VERSION 5.7 ;
BUSBITCHARS "[]" ;
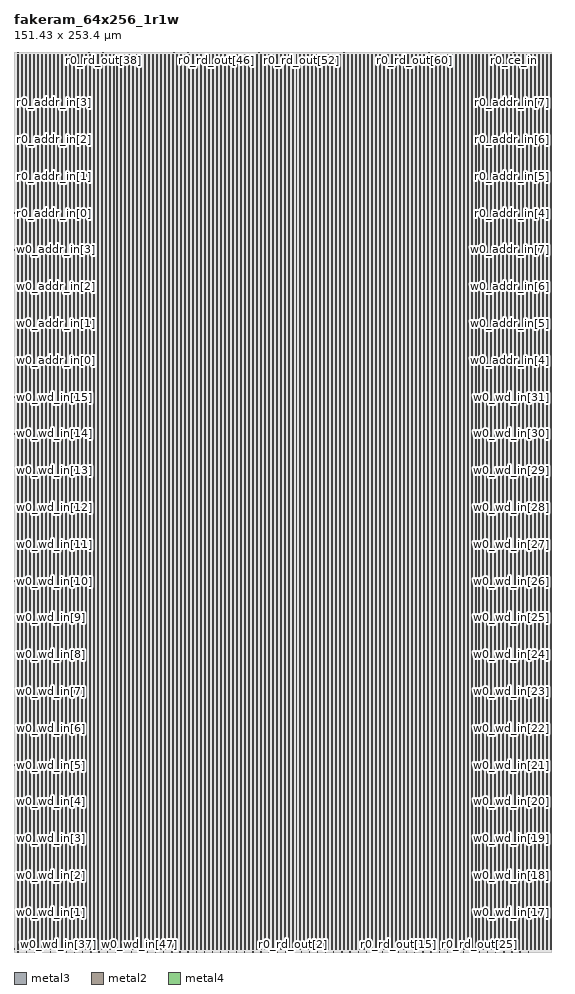
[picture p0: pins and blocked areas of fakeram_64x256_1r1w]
MACRO fakeram_64x256_1r1w
  FOREIGN fakeram_64x256_1r1w 0 0 ;
  SYMMETRY X Y R90 ;
  SIZE 151.430 BY 253.400 ;
  CLASS BLOCK ;
  PIN w0_wd_in[0]
    DIRECTION INPUT ;
    USE SIGNAL ;
    SHAPE ABUTMENT ;
    PORT
      LAYER metal3 ;
      RECT 0.000 0.805 0.210 0.875 ;
    END
  END w0_wd_in[0]
  PIN w0_wd_in[1]
    DIRECTION INPUT ;
    USE SIGNAL ;
    SHAPE ABUTMENT ;
    PORT
      LAYER metal3 ;
      RECT 0.000 11.165 0.210 11.235 ;
    END
  END w0_wd_in[1]
  PIN w0_wd_in[2]
    DIRECTION INPUT ;
    USE SIGNAL ;
    SHAPE ABUTMENT ;
    PORT
      LAYER metal3 ;
      RECT 0.000 21.525 0.210 21.595 ;
    END
  END w0_wd_in[2]
  PIN w0_wd_in[3]
    DIRECTION INPUT ;
    USE SIGNAL ;
    SHAPE ABUTMENT ;
    PORT
      LAYER metal3 ;
      RECT 0.000 31.885 0.210 31.955 ;
    END
  END w0_wd_in[3]
  PIN w0_wd_in[4]
    DIRECTION INPUT ;
    USE SIGNAL ;
    SHAPE ABUTMENT ;
    PORT
      LAYER metal3 ;
      RECT 0.000 42.245 0.210 42.315 ;
    END
  END w0_wd_in[4]
  PIN w0_wd_in[5]
    DIRECTION INPUT ;
    USE SIGNAL ;
    SHAPE ABUTMENT ;
    PORT
      LAYER metal3 ;
      RECT 0.000 52.605 0.210 52.675 ;
    END
  END w0_wd_in[5]
  PIN w0_wd_in[6]
    DIRECTION INPUT ;
    USE SIGNAL ;
    SHAPE ABUTMENT ;
    PORT
      LAYER metal3 ;
      RECT 0.000 62.965 0.210 63.035 ;
    END
  END w0_wd_in[6]
  PIN w0_wd_in[7]
    DIRECTION INPUT ;
    USE SIGNAL ;
    SHAPE ABUTMENT ;
    PORT
      LAYER metal3 ;
      RECT 0.000 73.325 0.210 73.395 ;
    END
  END w0_wd_in[7]
  PIN w0_wd_in[8]
    DIRECTION INPUT ;
    USE SIGNAL ;
    SHAPE ABUTMENT ;
    PORT
      LAYER metal3 ;
      RECT 0.000 83.685 0.210 83.755 ;
    END
  END w0_wd_in[8]
  PIN w0_wd_in[9]
    DIRECTION INPUT ;
    USE SIGNAL ;
    SHAPE ABUTMENT ;
    PORT
      LAYER metal3 ;
      RECT 0.000 94.045 0.210 94.115 ;
    END
  END w0_wd_in[9]
  PIN w0_wd_in[10]
    DIRECTION INPUT ;
    USE SIGNAL ;
    SHAPE ABUTMENT ;
    PORT
      LAYER metal3 ;
      RECT 0.000 104.405 0.210 104.475 ;
    END
  END w0_wd_in[10]
  PIN w0_wd_in[11]
    DIRECTION INPUT ;
    USE SIGNAL ;
    SHAPE ABUTMENT ;
    PORT
      LAYER metal3 ;
      RECT 0.000 114.765 0.210 114.835 ;
    END
  END w0_wd_in[11]
  PIN w0_wd_in[12]
    DIRECTION INPUT ;
    USE SIGNAL ;
    SHAPE ABUTMENT ;
    PORT
      LAYER metal3 ;
      RECT 0.000 125.125 0.210 125.195 ;
    END
  END w0_wd_in[12]
  PIN w0_wd_in[13]
    DIRECTION INPUT ;
    USE SIGNAL ;
    SHAPE ABUTMENT ;
    PORT
      LAYER metal3 ;
      RECT 0.000 135.485 0.210 135.555 ;
    END
  END w0_wd_in[13]
  PIN w0_wd_in[14]
    DIRECTION INPUT ;
    USE SIGNAL ;
    SHAPE ABUTMENT ;
    PORT
      LAYER metal3 ;
      RECT 0.000 145.845 0.210 145.915 ;
    END
  END w0_wd_in[14]
  PIN w0_wd_in[15]
    DIRECTION INPUT ;
    USE SIGNAL ;
    SHAPE ABUTMENT ;
    PORT
      LAYER metal3 ;
      RECT 0.000 156.205 0.210 156.275 ;
    END
  END w0_wd_in[15]
  PIN w0_wd_in[16]
    DIRECTION INPUT ;
    USE SIGNAL ;
    SHAPE ABUTMENT ;
    PORT
      LAYER metal3 ;
      RECT 151.220 0.805 151.430 0.875 ;
    END
  END w0_wd_in[16]
  PIN w0_wd_in[17]
    DIRECTION INPUT ;
    USE SIGNAL ;
    SHAPE ABUTMENT ;
    PORT
      LAYER metal3 ;
      RECT 151.220 11.165 151.430 11.235 ;
    END
  END w0_wd_in[17]
  PIN w0_wd_in[18]
    DIRECTION INPUT ;
    USE SIGNAL ;
    SHAPE ABUTMENT ;
    PORT
      LAYER metal3 ;
      RECT 151.220 21.525 151.430 21.595 ;
    END
  END w0_wd_in[18]
  PIN w0_wd_in[19]
    DIRECTION INPUT ;
    USE SIGNAL ;
    SHAPE ABUTMENT ;
    PORT
      LAYER metal3 ;
      RECT 151.220 31.885 151.430 31.955 ;
    END
  END w0_wd_in[19]
  PIN w0_wd_in[20]
    DIRECTION INPUT ;
    USE SIGNAL ;
    SHAPE ABUTMENT ;
    PORT
      LAYER metal3 ;
      RECT 151.220 42.245 151.430 42.315 ;
    END
  END w0_wd_in[20]
  PIN w0_wd_in[21]
    DIRECTION INPUT ;
    USE SIGNAL ;
    SHAPE ABUTMENT ;
    PORT
      LAYER metal3 ;
      RECT 151.220 52.605 151.430 52.675 ;
    END
  END w0_wd_in[21]
  PIN w0_wd_in[22]
    DIRECTION INPUT ;
    USE SIGNAL ;
    SHAPE ABUTMENT ;
    PORT
      LAYER metal3 ;
      RECT 151.220 62.965 151.430 63.035 ;
    END
  END w0_wd_in[22]
  PIN w0_wd_in[23]
    DIRECTION INPUT ;
    USE SIGNAL ;
    SHAPE ABUTMENT ;
    PORT
      LAYER metal3 ;
      RECT 151.220 73.325 151.430 73.395 ;
    END
  END w0_wd_in[23]
  PIN w0_wd_in[24]
    DIRECTION INPUT ;
    USE SIGNAL ;
    SHAPE ABUTMENT ;
    PORT
      LAYER metal3 ;
      RECT 151.220 83.685 151.430 83.755 ;
    END
  END w0_wd_in[24]
  PIN w0_wd_in[25]
    DIRECTION INPUT ;
    USE SIGNAL ;
    SHAPE ABUTMENT ;
    PORT
      LAYER metal3 ;
      RECT 151.220 94.045 151.430 94.115 ;
    END
  END w0_wd_in[25]
  PIN w0_wd_in[26]
    DIRECTION INPUT ;
    USE SIGNAL ;
    SHAPE ABUTMENT ;
    PORT
      LAYER metal3 ;
      RECT 151.220 104.405 151.430 104.475 ;
    END
  END w0_wd_in[26]
  PIN w0_wd_in[27]
    DIRECTION INPUT ;
    USE SIGNAL ;
    SHAPE ABUTMENT ;
    PORT
      LAYER metal3 ;
      RECT 151.220 114.765 151.430 114.835 ;
    END
  END w0_wd_in[27]
  PIN w0_wd_in[28]
    DIRECTION INPUT ;
    USE SIGNAL ;
    SHAPE ABUTMENT ;
    PORT
      LAYER metal3 ;
      RECT 151.220 125.125 151.430 125.195 ;
    END
  END w0_wd_in[28]
  PIN w0_wd_in[29]
    DIRECTION INPUT ;
    USE SIGNAL ;
    SHAPE ABUTMENT ;
    PORT
      LAYER metal3 ;
      RECT 151.220 135.485 151.430 135.555 ;
    END
  END w0_wd_in[29]
  PIN w0_wd_in[30]
    DIRECTION INPUT ;
    USE SIGNAL ;
    SHAPE ABUTMENT ;
    PORT
      LAYER metal3 ;
      RECT 151.220 145.845 151.430 145.915 ;
    END
  END w0_wd_in[30]
  PIN w0_wd_in[31]
    DIRECTION INPUT ;
    USE SIGNAL ;
    SHAPE ABUTMENT ;
    PORT
      LAYER metal3 ;
      RECT 151.220 156.205 151.430 156.275 ;
    END
  END w0_wd_in[31]
  PIN w0_wd_in[32]
    DIRECTION INPUT ;
    USE SIGNAL ;
    SHAPE ABUTMENT ;
    PORT
      LAYER metal2 ;
      RECT 1.105 0.000 1.175 0.210 ;
    END
  END w0_wd_in[32]
  PIN w0_wd_in[33]
    DIRECTION INPUT ;
    USE SIGNAL ;
    SHAPE ABUTMENT ;
    PORT
      LAYER metal2 ;
      RECT 3.385 0.000 3.455 0.210 ;
    END
  END w0_wd_in[33]
  PIN w0_wd_in[34]
    DIRECTION INPUT ;
    USE SIGNAL ;
    SHAPE ABUTMENT ;
    PORT
      LAYER metal2 ;
      RECT 5.665 0.000 5.735 0.210 ;
    END
  END w0_wd_in[34]
  PIN w0_wd_in[35]
    DIRECTION INPUT ;
    USE SIGNAL ;
    SHAPE ABUTMENT ;
    PORT
      LAYER metal2 ;
      RECT 7.945 0.000 8.015 0.210 ;
    END
  END w0_wd_in[35]
  PIN w0_wd_in[36]
    DIRECTION INPUT ;
    USE SIGNAL ;
    SHAPE ABUTMENT ;
    PORT
      LAYER metal2 ;
      RECT 10.225 0.000 10.295 0.210 ;
    END
  END w0_wd_in[36]
  PIN w0_wd_in[37]
    DIRECTION INPUT ;
    USE SIGNAL ;
    SHAPE ABUTMENT ;
    PORT
      LAYER metal2 ;
      RECT 12.505 0.000 12.575 0.210 ;
    END
  END w0_wd_in[37]
  PIN w0_wd_in[38]
    DIRECTION INPUT ;
    USE SIGNAL ;
    SHAPE ABUTMENT ;
    PORT
      LAYER metal2 ;
      RECT 14.785 0.000 14.855 0.210 ;
    END
  END w0_wd_in[38]
  PIN w0_wd_in[39]
    DIRECTION INPUT ;
    USE SIGNAL ;
    SHAPE ABUTMENT ;
    PORT
      LAYER metal2 ;
      RECT 17.065 0.000 17.135 0.210 ;
    END
  END w0_wd_in[39]
  PIN w0_wd_in[40]
    DIRECTION INPUT ;
    USE SIGNAL ;
    SHAPE ABUTMENT ;
    PORT
      LAYER metal2 ;
      RECT 19.345 0.000 19.415 0.210 ;
    END
  END w0_wd_in[40]
  PIN w0_wd_in[41]
    DIRECTION INPUT ;
    USE SIGNAL ;
    SHAPE ABUTMENT ;
    PORT
      LAYER metal2 ;
      RECT 21.625 0.000 21.695 0.210 ;
    END
  END w0_wd_in[41]
  PIN w0_wd_in[42]
    DIRECTION INPUT ;
    USE SIGNAL ;
    SHAPE ABUTMENT ;
    PORT
      LAYER metal2 ;
      RECT 23.905 0.000 23.975 0.210 ;
    END
  END w0_wd_in[42]
  PIN w0_wd_in[43]
    DIRECTION INPUT ;
    USE SIGNAL ;
    SHAPE ABUTMENT ;
    PORT
      LAYER metal2 ;
      RECT 26.185 0.000 26.255 0.210 ;
    END
  END w0_wd_in[43]
  PIN w0_wd_in[44]
    DIRECTION INPUT ;
    USE SIGNAL ;
    SHAPE ABUTMENT ;
    PORT
      LAYER metal2 ;
      RECT 28.465 0.000 28.535 0.210 ;
    END
  END w0_wd_in[44]
  PIN w0_wd_in[45]
    DIRECTION INPUT ;
    USE SIGNAL ;
    SHAPE ABUTMENT ;
    PORT
      LAYER metal2 ;
      RECT 30.745 0.000 30.815 0.210 ;
    END
  END w0_wd_in[45]
  PIN w0_wd_in[46]
    DIRECTION INPUT ;
    USE SIGNAL ;
    SHAPE ABUTMENT ;
    PORT
      LAYER metal2 ;
      RECT 33.025 0.000 33.095 0.210 ;
    END
  END w0_wd_in[46]
  PIN w0_wd_in[47]
    DIRECTION INPUT ;
    USE SIGNAL ;
    SHAPE ABUTMENT ;
    PORT
      LAYER metal2 ;
      RECT 35.305 0.000 35.375 0.210 ;
    END
  END w0_wd_in[47]
  PIN w0_wd_in[48]
    DIRECTION INPUT ;
    USE SIGNAL ;
    SHAPE ABUTMENT ;
    PORT
      LAYER metal2 ;
      RECT 37.585 0.000 37.655 0.210 ;
    END
  END w0_wd_in[48]
  PIN w0_wd_in[49]
    DIRECTION INPUT ;
    USE SIGNAL ;
    SHAPE ABUTMENT ;
    PORT
      LAYER metal2 ;
      RECT 39.865 0.000 39.935 0.210 ;
    END
  END w0_wd_in[49]
  PIN w0_wd_in[50]
    DIRECTION INPUT ;
    USE SIGNAL ;
    SHAPE ABUTMENT ;
    PORT
      LAYER metal2 ;
      RECT 42.145 0.000 42.215 0.210 ;
    END
  END w0_wd_in[50]
  PIN w0_wd_in[51]
    DIRECTION INPUT ;
    USE SIGNAL ;
    SHAPE ABUTMENT ;
    PORT
      LAYER metal2 ;
      RECT 44.425 0.000 44.495 0.210 ;
    END
  END w0_wd_in[51]
  PIN w0_wd_in[52]
    DIRECTION INPUT ;
    USE SIGNAL ;
    SHAPE ABUTMENT ;
    PORT
      LAYER metal2 ;
      RECT 46.705 0.000 46.775 0.210 ;
    END
  END w0_wd_in[52]
  PIN w0_wd_in[53]
    DIRECTION INPUT ;
    USE SIGNAL ;
    SHAPE ABUTMENT ;
    PORT
      LAYER metal2 ;
      RECT 48.985 0.000 49.055 0.210 ;
    END
  END w0_wd_in[53]
  PIN w0_wd_in[54]
    DIRECTION INPUT ;
    USE SIGNAL ;
    SHAPE ABUTMENT ;
    PORT
      LAYER metal2 ;
      RECT 51.265 0.000 51.335 0.210 ;
    END
  END w0_wd_in[54]
  PIN w0_wd_in[55]
    DIRECTION INPUT ;
    USE SIGNAL ;
    SHAPE ABUTMENT ;
    PORT
      LAYER metal2 ;
      RECT 53.545 0.000 53.615 0.210 ;
    END
  END w0_wd_in[55]
  PIN w0_wd_in[56]
    DIRECTION INPUT ;
    USE SIGNAL ;
    SHAPE ABUTMENT ;
    PORT
      LAYER metal2 ;
      RECT 55.825 0.000 55.895 0.210 ;
    END
  END w0_wd_in[56]
  PIN w0_wd_in[57]
    DIRECTION INPUT ;
    USE SIGNAL ;
    SHAPE ABUTMENT ;
    PORT
      LAYER metal2 ;
      RECT 58.105 0.000 58.175 0.210 ;
    END
  END w0_wd_in[57]
  PIN w0_wd_in[58]
    DIRECTION INPUT ;
    USE SIGNAL ;
    SHAPE ABUTMENT ;
    PORT
      LAYER metal2 ;
      RECT 60.385 0.000 60.455 0.210 ;
    END
  END w0_wd_in[58]
  PIN w0_wd_in[59]
    DIRECTION INPUT ;
    USE SIGNAL ;
    SHAPE ABUTMENT ;
    PORT
      LAYER metal2 ;
      RECT 62.665 0.000 62.735 0.210 ;
    END
  END w0_wd_in[59]
  PIN w0_wd_in[60]
    DIRECTION INPUT ;
    USE SIGNAL ;
    SHAPE ABUTMENT ;
    PORT
      LAYER metal2 ;
      RECT 64.945 0.000 65.015 0.210 ;
    END
  END w0_wd_in[60]
  PIN w0_wd_in[61]
    DIRECTION INPUT ;
    USE SIGNAL ;
    SHAPE ABUTMENT ;
    PORT
      LAYER metal2 ;
      RECT 67.225 0.000 67.295 0.210 ;
    END
  END w0_wd_in[61]
  PIN w0_wd_in[62]
    DIRECTION INPUT ;
    USE SIGNAL ;
    SHAPE ABUTMENT ;
    PORT
      LAYER metal2 ;
      RECT 69.505 0.000 69.575 0.210 ;
    END
  END w0_wd_in[62]
  PIN w0_wd_in[63]
    DIRECTION INPUT ;
    USE SIGNAL ;
    SHAPE ABUTMENT ;
    PORT
      LAYER metal2 ;
      RECT 71.785 0.000 71.855 0.210 ;
    END
  END w0_wd_in[63]
  PIN r0_rd_out[0]
    DIRECTION OUTPUT ;
    USE SIGNAL ;
    SHAPE ABUTMENT ;
    PORT
      LAYER metal2 ;
      RECT 74.065 0.000 74.135 0.210 ;
    END
  END r0_rd_out[0]
  PIN r0_rd_out[1]
    DIRECTION OUTPUT ;
    USE SIGNAL ;
    SHAPE ABUTMENT ;
    PORT
      LAYER metal2 ;
      RECT 76.345 0.000 76.415 0.210 ;
    END
  END r0_rd_out[1]
  PIN r0_rd_out[2]
    DIRECTION OUTPUT ;
    USE SIGNAL ;
    SHAPE ABUTMENT ;
    PORT
      LAYER metal2 ;
      RECT 78.625 0.000 78.695 0.210 ;
    END
  END r0_rd_out[2]
  PIN r0_rd_out[3]
    DIRECTION OUTPUT ;
    USE SIGNAL ;
    SHAPE ABUTMENT ;
    PORT
      LAYER metal2 ;
      RECT 80.905 0.000 80.975 0.210 ;
    END
  END r0_rd_out[3]
  PIN r0_rd_out[4]
    DIRECTION OUTPUT ;
    USE SIGNAL ;
    SHAPE ABUTMENT ;
    PORT
      LAYER metal2 ;
      RECT 83.185 0.000 83.255 0.210 ;
    END
  END r0_rd_out[4]
  PIN r0_rd_out[5]
    DIRECTION OUTPUT ;
    USE SIGNAL ;
    SHAPE ABUTMENT ;
    PORT
      LAYER metal2 ;
      RECT 85.465 0.000 85.535 0.210 ;
    END
  END r0_rd_out[5]
  PIN r0_rd_out[6]
    DIRECTION OUTPUT ;
    USE SIGNAL ;
    SHAPE ABUTMENT ;
    PORT
      LAYER metal2 ;
      RECT 87.745 0.000 87.815 0.210 ;
    END
  END r0_rd_out[6]
  PIN r0_rd_out[7]
    DIRECTION OUTPUT ;
    USE SIGNAL ;
    SHAPE ABUTMENT ;
    PORT
      LAYER metal2 ;
      RECT 90.025 0.000 90.095 0.210 ;
    END
  END r0_rd_out[7]
  PIN r0_rd_out[8]
    DIRECTION OUTPUT ;
    USE SIGNAL ;
    SHAPE ABUTMENT ;
    PORT
      LAYER metal2 ;
      RECT 92.305 0.000 92.375 0.210 ;
    END
  END r0_rd_out[8]
  PIN r0_rd_out[9]
    DIRECTION OUTPUT ;
    USE SIGNAL ;
    SHAPE ABUTMENT ;
    PORT
      LAYER metal2 ;
      RECT 94.585 0.000 94.655 0.210 ;
    END
  END r0_rd_out[9]
  PIN r0_rd_out[10]
    DIRECTION OUTPUT ;
    USE SIGNAL ;
    SHAPE ABUTMENT ;
    PORT
      LAYER metal2 ;
      RECT 96.865 0.000 96.935 0.210 ;
    END
  END r0_rd_out[10]
  PIN r0_rd_out[11]
    DIRECTION OUTPUT ;
    USE SIGNAL ;
    SHAPE ABUTMENT ;
    PORT
      LAYER metal2 ;
      RECT 99.145 0.000 99.215 0.210 ;
    END
  END r0_rd_out[11]
  PIN r0_rd_out[12]
    DIRECTION OUTPUT ;
    USE SIGNAL ;
    SHAPE ABUTMENT ;
    PORT
      LAYER metal2 ;
      RECT 101.425 0.000 101.495 0.210 ;
    END
  END r0_rd_out[12]
  PIN r0_rd_out[13]
    DIRECTION OUTPUT ;
    USE SIGNAL ;
    SHAPE ABUTMENT ;
    PORT
      LAYER metal2 ;
      RECT 103.705 0.000 103.775 0.210 ;
    END
  END r0_rd_out[13]
  PIN r0_rd_out[14]
    DIRECTION OUTPUT ;
    USE SIGNAL ;
    SHAPE ABUTMENT ;
    PORT
      LAYER metal2 ;
      RECT 105.985 0.000 106.055 0.210 ;
    END
  END r0_rd_out[14]
  PIN r0_rd_out[15]
    DIRECTION OUTPUT ;
    USE SIGNAL ;
    SHAPE ABUTMENT ;
    PORT
      LAYER metal2 ;
      RECT 108.265 0.000 108.335 0.210 ;
    END
  END r0_rd_out[15]
  PIN r0_rd_out[16]
    DIRECTION OUTPUT ;
    USE SIGNAL ;
    SHAPE ABUTMENT ;
    PORT
      LAYER metal2 ;
      RECT 110.545 0.000 110.615 0.210 ;
    END
  END r0_rd_out[16]
  PIN r0_rd_out[17]
    DIRECTION OUTPUT ;
    USE SIGNAL ;
    SHAPE ABUTMENT ;
    PORT
      LAYER metal2 ;
      RECT 112.825 0.000 112.895 0.210 ;
    END
  END r0_rd_out[17]
  PIN r0_rd_out[18]
    DIRECTION OUTPUT ;
    USE SIGNAL ;
    SHAPE ABUTMENT ;
    PORT
      LAYER metal2 ;
      RECT 115.105 0.000 115.175 0.210 ;
    END
  END r0_rd_out[18]
  PIN r0_rd_out[19]
    DIRECTION OUTPUT ;
    USE SIGNAL ;
    SHAPE ABUTMENT ;
    PORT
      LAYER metal2 ;
      RECT 117.385 0.000 117.455 0.210 ;
    END
  END r0_rd_out[19]
  PIN r0_rd_out[20]
    DIRECTION OUTPUT ;
    USE SIGNAL ;
    SHAPE ABUTMENT ;
    PORT
      LAYER metal2 ;
      RECT 119.665 0.000 119.735 0.210 ;
    END
  END r0_rd_out[20]
  PIN r0_rd_out[21]
    DIRECTION OUTPUT ;
    USE SIGNAL ;
    SHAPE ABUTMENT ;
    PORT
      LAYER metal2 ;
      RECT 121.945 0.000 122.015 0.210 ;
    END
  END r0_rd_out[21]
  PIN r0_rd_out[22]
    DIRECTION OUTPUT ;
    USE SIGNAL ;
    SHAPE ABUTMENT ;
    PORT
      LAYER metal2 ;
      RECT 124.225 0.000 124.295 0.210 ;
    END
  END r0_rd_out[22]
  PIN r0_rd_out[23]
    DIRECTION OUTPUT ;
    USE SIGNAL ;
    SHAPE ABUTMENT ;
    PORT
      LAYER metal2 ;
      RECT 126.505 0.000 126.575 0.210 ;
    END
  END r0_rd_out[23]
  PIN r0_rd_out[24]
    DIRECTION OUTPUT ;
    USE SIGNAL ;
    SHAPE ABUTMENT ;
    PORT
      LAYER metal2 ;
      RECT 128.785 0.000 128.855 0.210 ;
    END
  END r0_rd_out[24]
  PIN r0_rd_out[25]
    DIRECTION OUTPUT ;
    USE SIGNAL ;
    SHAPE ABUTMENT ;
    PORT
      LAYER metal2 ;
      RECT 131.065 0.000 131.135 0.210 ;
    END
  END r0_rd_out[25]
  PIN r0_rd_out[26]
    DIRECTION OUTPUT ;
    USE SIGNAL ;
    SHAPE ABUTMENT ;
    PORT
      LAYER metal2 ;
      RECT 133.345 0.000 133.415 0.210 ;
    END
  END r0_rd_out[26]
  PIN r0_rd_out[27]
    DIRECTION OUTPUT ;
    USE SIGNAL ;
    SHAPE ABUTMENT ;
    PORT
      LAYER metal2 ;
      RECT 135.625 0.000 135.695 0.210 ;
    END
  END r0_rd_out[27]
  PIN r0_rd_out[28]
    DIRECTION OUTPUT ;
    USE SIGNAL ;
    SHAPE ABUTMENT ;
    PORT
      LAYER metal2 ;
      RECT 137.905 0.000 137.975 0.210 ;
    END
  END r0_rd_out[28]
  PIN r0_rd_out[29]
    DIRECTION OUTPUT ;
    USE SIGNAL ;
    SHAPE ABUTMENT ;
    PORT
      LAYER metal2 ;
      RECT 140.185 0.000 140.255 0.210 ;
    END
  END r0_rd_out[29]
  PIN r0_rd_out[30]
    DIRECTION OUTPUT ;
    USE SIGNAL ;
    SHAPE ABUTMENT ;
    PORT
      LAYER metal2 ;
      RECT 142.465 0.000 142.535 0.210 ;
    END
  END r0_rd_out[30]
  PIN r0_rd_out[31]
    DIRECTION OUTPUT ;
    USE SIGNAL ;
    SHAPE ABUTMENT ;
    PORT
      LAYER metal2 ;
      RECT 144.745 0.000 144.815 0.210 ;
    END
  END r0_rd_out[31]
  PIN r0_rd_out[32]
    DIRECTION OUTPUT ;
    USE SIGNAL ;
    SHAPE ABUTMENT ;
    PORT
      LAYER metal2 ;
      RECT 1.105 253.190 1.175 253.400 ;
    END
  END r0_rd_out[32]
  PIN r0_rd_out[33]
    DIRECTION OUTPUT ;
    USE SIGNAL ;
    SHAPE ABUTMENT ;
    PORT
      LAYER metal2 ;
      RECT 5.095 253.190 5.165 253.400 ;
    END
  END r0_rd_out[33]
  PIN r0_rd_out[34]
    DIRECTION OUTPUT ;
    USE SIGNAL ;
    SHAPE ABUTMENT ;
    PORT
      LAYER metal2 ;
      RECT 9.085 253.190 9.155 253.400 ;
    END
  END r0_rd_out[34]
  PIN r0_rd_out[35]
    DIRECTION OUTPUT ;
    USE SIGNAL ;
    SHAPE ABUTMENT ;
    PORT
      LAYER metal2 ;
      RECT 13.075 253.190 13.145 253.400 ;
    END
  END r0_rd_out[35]
  PIN r0_rd_out[36]
    DIRECTION OUTPUT ;
    USE SIGNAL ;
    SHAPE ABUTMENT ;
    PORT
      LAYER metal2 ;
      RECT 17.065 253.190 17.135 253.400 ;
    END
  END r0_rd_out[36]
  PIN r0_rd_out[37]
    DIRECTION OUTPUT ;
    USE SIGNAL ;
    SHAPE ABUTMENT ;
    PORT
      LAYER metal2 ;
      RECT 21.055 253.190 21.125 253.400 ;
    END
  END r0_rd_out[37]
  PIN r0_rd_out[38]
    DIRECTION OUTPUT ;
    USE SIGNAL ;
    SHAPE ABUTMENT ;
    PORT
      LAYER metal2 ;
      RECT 25.045 253.190 25.115 253.400 ;
    END
  END r0_rd_out[38]
  PIN r0_rd_out[39]
    DIRECTION OUTPUT ;
    USE SIGNAL ;
    SHAPE ABUTMENT ;
    PORT
      LAYER metal2 ;
      RECT 29.035 253.190 29.105 253.400 ;
    END
  END r0_rd_out[39]
  PIN r0_rd_out[40]
    DIRECTION OUTPUT ;
    USE SIGNAL ;
    SHAPE ABUTMENT ;
    PORT
      LAYER metal2 ;
      RECT 33.025 253.190 33.095 253.400 ;
    END
  END r0_rd_out[40]
  PIN r0_rd_out[41]
    DIRECTION OUTPUT ;
    USE SIGNAL ;
    SHAPE ABUTMENT ;
    PORT
      LAYER metal2 ;
      RECT 37.015 253.190 37.085 253.400 ;
    END
  END r0_rd_out[41]
  PIN r0_rd_out[42]
    DIRECTION OUTPUT ;
    USE SIGNAL ;
    SHAPE ABUTMENT ;
    PORT
      LAYER metal2 ;
      RECT 41.005 253.190 41.075 253.400 ;
    END
  END r0_rd_out[42]
  PIN r0_rd_out[43]
    DIRECTION OUTPUT ;
    USE SIGNAL ;
    SHAPE ABUTMENT ;
    PORT
      LAYER metal2 ;
      RECT 44.995 253.190 45.065 253.400 ;
    END
  END r0_rd_out[43]
  PIN r0_rd_out[44]
    DIRECTION OUTPUT ;
    USE SIGNAL ;
    SHAPE ABUTMENT ;
    PORT
      LAYER metal2 ;
      RECT 48.985 253.190 49.055 253.400 ;
    END
  END r0_rd_out[44]
  PIN r0_rd_out[45]
    DIRECTION OUTPUT ;
    USE SIGNAL ;
    SHAPE ABUTMENT ;
    PORT
      LAYER metal2 ;
      RECT 52.975 253.190 53.045 253.400 ;
    END
  END r0_rd_out[45]
  PIN r0_rd_out[46]
    DIRECTION OUTPUT ;
    USE SIGNAL ;
    SHAPE ABUTMENT ;
    PORT
      LAYER metal2 ;
      RECT 56.965 253.190 57.035 253.400 ;
    END
  END r0_rd_out[46]
  PIN r0_rd_out[47]
    DIRECTION OUTPUT ;
    USE SIGNAL ;
    SHAPE ABUTMENT ;
    PORT
      LAYER metal2 ;
      RECT 60.955 253.190 61.025 253.400 ;
    END
  END r0_rd_out[47]
  PIN r0_rd_out[48]
    DIRECTION OUTPUT ;
    USE SIGNAL ;
    SHAPE ABUTMENT ;
    PORT
      LAYER metal2 ;
      RECT 64.945 253.190 65.015 253.400 ;
    END
  END r0_rd_out[48]
  PIN r0_rd_out[49]
    DIRECTION OUTPUT ;
    USE SIGNAL ;
    SHAPE ABUTMENT ;
    PORT
      LAYER metal2 ;
      RECT 68.935 253.190 69.005 253.400 ;
    END
  END r0_rd_out[49]
  PIN r0_rd_out[50]
    DIRECTION OUTPUT ;
    USE SIGNAL ;
    SHAPE ABUTMENT ;
    PORT
      LAYER metal2 ;
      RECT 72.925 253.190 72.995 253.400 ;
    END
  END r0_rd_out[50]
  PIN r0_rd_out[51]
    DIRECTION OUTPUT ;
    USE SIGNAL ;
    SHAPE ABUTMENT ;
    PORT
      LAYER metal2 ;
      RECT 76.915 253.190 76.985 253.400 ;
    END
  END r0_rd_out[51]
  PIN r0_rd_out[52]
    DIRECTION OUTPUT ;
    USE SIGNAL ;
    SHAPE ABUTMENT ;
    PORT
      LAYER metal2 ;
      RECT 80.905 253.190 80.975 253.400 ;
    END
  END r0_rd_out[52]
  PIN r0_rd_out[53]
    DIRECTION OUTPUT ;
    USE SIGNAL ;
    SHAPE ABUTMENT ;
    PORT
      LAYER metal2 ;
      RECT 84.895 253.190 84.965 253.400 ;
    END
  END r0_rd_out[53]
  PIN r0_rd_out[54]
    DIRECTION OUTPUT ;
    USE SIGNAL ;
    SHAPE ABUTMENT ;
    PORT
      LAYER metal2 ;
      RECT 88.885 253.190 88.955 253.400 ;
    END
  END r0_rd_out[54]
  PIN r0_rd_out[55]
    DIRECTION OUTPUT ;
    USE SIGNAL ;
    SHAPE ABUTMENT ;
    PORT
      LAYER metal2 ;
      RECT 92.875 253.190 92.945 253.400 ;
    END
  END r0_rd_out[55]
  PIN r0_rd_out[56]
    DIRECTION OUTPUT ;
    USE SIGNAL ;
    SHAPE ABUTMENT ;
    PORT
      LAYER metal2 ;
      RECT 96.865 253.190 96.935 253.400 ;
    END
  END r0_rd_out[56]
  PIN r0_rd_out[57]
    DIRECTION OUTPUT ;
    USE SIGNAL ;
    SHAPE ABUTMENT ;
    PORT
      LAYER metal2 ;
      RECT 100.855 253.190 100.925 253.400 ;
    END
  END r0_rd_out[57]
  PIN r0_rd_out[58]
    DIRECTION OUTPUT ;
    USE SIGNAL ;
    SHAPE ABUTMENT ;
    PORT
      LAYER metal2 ;
      RECT 104.845 253.190 104.915 253.400 ;
    END
  END r0_rd_out[58]
  PIN r0_rd_out[59]
    DIRECTION OUTPUT ;
    USE SIGNAL ;
    SHAPE ABUTMENT ;
    PORT
      LAYER metal2 ;
      RECT 108.835 253.190 108.905 253.400 ;
    END
  END r0_rd_out[59]
  PIN r0_rd_out[60]
    DIRECTION OUTPUT ;
    USE SIGNAL ;
    SHAPE ABUTMENT ;
    PORT
      LAYER metal2 ;
      RECT 112.825 253.190 112.895 253.400 ;
    END
  END r0_rd_out[60]
  PIN r0_rd_out[61]
    DIRECTION OUTPUT ;
    USE SIGNAL ;
    SHAPE ABUTMENT ;
    PORT
      LAYER metal2 ;
      RECT 116.815 253.190 116.885 253.400 ;
    END
  END r0_rd_out[61]
  PIN r0_rd_out[62]
    DIRECTION OUTPUT ;
    USE SIGNAL ;
    SHAPE ABUTMENT ;
    PORT
      LAYER metal2 ;
      RECT 120.805 253.190 120.875 253.400 ;
    END
  END r0_rd_out[62]
  PIN r0_rd_out[63]
    DIRECTION OUTPUT ;
    USE SIGNAL ;
    SHAPE ABUTMENT ;
    PORT
      LAYER metal2 ;
      RECT 124.795 253.190 124.865 253.400 ;
    END
  END r0_rd_out[63]
  PIN w0_addr_in[0]
    DIRECTION INPUT ;
    USE SIGNAL ;
    SHAPE ABUTMENT ;
    PORT
      LAYER metal3 ;
      RECT 0.000 166.565 0.210 166.635 ;
    END
  END w0_addr_in[0]
  PIN w0_addr_in[1]
    DIRECTION INPUT ;
    USE SIGNAL ;
    SHAPE ABUTMENT ;
    PORT
      LAYER metal3 ;
      RECT 0.000 176.925 0.210 176.995 ;
    END
  END w0_addr_in[1]
  PIN w0_addr_in[2]
    DIRECTION INPUT ;
    USE SIGNAL ;
    SHAPE ABUTMENT ;
    PORT
      LAYER metal3 ;
      RECT 0.000 187.285 0.210 187.355 ;
    END
  END w0_addr_in[2]
  PIN w0_addr_in[3]
    DIRECTION INPUT ;
    USE SIGNAL ;
    SHAPE ABUTMENT ;
    PORT
      LAYER metal3 ;
      RECT 0.000 197.645 0.210 197.715 ;
    END
  END w0_addr_in[3]
  PIN w0_addr_in[4]
    DIRECTION INPUT ;
    USE SIGNAL ;
    SHAPE ABUTMENT ;
    PORT
      LAYER metal3 ;
      RECT 151.220 166.565 151.430 166.635 ;
    END
  END w0_addr_in[4]
  PIN w0_addr_in[5]
    DIRECTION INPUT ;
    USE SIGNAL ;
    SHAPE ABUTMENT ;
    PORT
      LAYER metal3 ;
      RECT 151.220 176.925 151.430 176.995 ;
    END
  END w0_addr_in[5]
  PIN w0_addr_in[6]
    DIRECTION INPUT ;
    USE SIGNAL ;
    SHAPE ABUTMENT ;
    PORT
      LAYER metal3 ;
      RECT 151.220 187.285 151.430 187.355 ;
    END
  END w0_addr_in[6]
  PIN w0_addr_in[7]
    DIRECTION INPUT ;
    USE SIGNAL ;
    SHAPE ABUTMENT ;
    PORT
      LAYER metal3 ;
      RECT 151.220 197.645 151.430 197.715 ;
    END
  END w0_addr_in[7]
  PIN r0_addr_in[0]
    DIRECTION INPUT ;
    USE SIGNAL ;
    SHAPE ABUTMENT ;
    PORT
      LAYER metal3 ;
      RECT 0.000 208.005 0.210 208.075 ;
    END
  END r0_addr_in[0]
  PIN r0_addr_in[1]
    DIRECTION INPUT ;
    USE SIGNAL ;
    SHAPE ABUTMENT ;
    PORT
      LAYER metal3 ;
      RECT 0.000 218.365 0.210 218.435 ;
    END
  END r0_addr_in[1]
  PIN r0_addr_in[2]
    DIRECTION INPUT ;
    USE SIGNAL ;
    SHAPE ABUTMENT ;
    PORT
      LAYER metal3 ;
      RECT 0.000 228.725 0.210 228.795 ;
    END
  END r0_addr_in[2]
  PIN r0_addr_in[3]
    DIRECTION INPUT ;
    USE SIGNAL ;
    SHAPE ABUTMENT ;
    PORT
      LAYER metal3 ;
      RECT 0.000 239.085 0.210 239.155 ;
    END
  END r0_addr_in[3]
  PIN r0_addr_in[4]
    DIRECTION INPUT ;
    USE SIGNAL ;
    SHAPE ABUTMENT ;
    PORT
      LAYER metal3 ;
      RECT 151.220 208.005 151.430 208.075 ;
    END
  END r0_addr_in[4]
  PIN r0_addr_in[5]
    DIRECTION INPUT ;
    USE SIGNAL ;
    SHAPE ABUTMENT ;
    PORT
      LAYER metal3 ;
      RECT 151.220 218.365 151.430 218.435 ;
    END
  END r0_addr_in[5]
  PIN r0_addr_in[6]
    DIRECTION INPUT ;
    USE SIGNAL ;
    SHAPE ABUTMENT ;
    PORT
      LAYER metal3 ;
      RECT 151.220 228.725 151.430 228.795 ;
    END
  END r0_addr_in[6]
  PIN r0_addr_in[7]
    DIRECTION INPUT ;
    USE SIGNAL ;
    SHAPE ABUTMENT ;
    PORT
      LAYER metal3 ;
      RECT 151.220 239.085 151.430 239.155 ;
    END
  END r0_addr_in[7]
  PIN w0_we_in
    DIRECTION INPUT ;
    USE SIGNAL ;
    SHAPE ABUTMENT ;
    PORT
      LAYER metal2 ;
      RECT 128.785 253.190 128.855 253.400 ;
    END
  END w0_we_in
  PIN w0_ce_in
    DIRECTION INPUT ;
    USE SIGNAL ;
    SHAPE ABUTMENT ;
    PORT
      LAYER metal2 ;
      RECT 132.775 253.190 132.845 253.400 ;
    END
  END w0_ce_in
  PIN w0_clk
    DIRECTION INPUT ;
    USE SIGNAL ;
    SHAPE ABUTMENT ;
    PORT
      LAYER metal2 ;
      RECT 136.765 253.190 136.835 253.400 ;
    END
  END w0_clk
  PIN r0_ce_in
    DIRECTION INPUT ;
    USE SIGNAL ;
    SHAPE ABUTMENT ;
    PORT
      LAYER metal2 ;
      RECT 140.755 253.190 140.825 253.400 ;
    END
  END r0_ce_in
  PIN r0_clk
    DIRECTION INPUT ;
    USE SIGNAL ;
    SHAPE ABUTMENT ;
    PORT
      LAYER metal2 ;
      RECT 144.745 253.190 144.815 253.400 ;
    END
  END r0_clk
  PIN VSS
    DIRECTION INOUT ;
    USE GROUND ;
    PORT
      LAYER metal4 ;
      RECT 1.000 0.840 1.280 252.560 ;
      RECT 3.240 0.840 3.520 252.560 ;
      RECT 5.480 0.840 5.760 252.560 ;
      RECT 7.720 0.840 8.000 252.560 ;
      RECT 9.960 0.840 10.240 252.560 ;
      RECT 12.200 0.840 12.480 252.560 ;
      RECT 14.440 0.840 14.720 252.560 ;
      RECT 16.680 0.840 16.960 252.560 ;
      RECT 18.920 0.840 19.200 252.560 ;
      RECT 21.160 0.840 21.440 252.560 ;
      RECT 23.400 0.840 23.680 252.560 ;
      RECT 25.640 0.840 25.920 252.560 ;
      RECT 27.880 0.840 28.160 252.560 ;
      RECT 30.120 0.840 30.400 252.560 ;
      RECT 32.360 0.840 32.640 252.560 ;
      RECT 34.600 0.840 34.880 252.560 ;
      RECT 36.840 0.840 37.120 252.560 ;
      RECT 39.080 0.840 39.360 252.560 ;
      RECT 41.320 0.840 41.600 252.560 ;
      RECT 43.560 0.840 43.840 252.560 ;
      RECT 45.800 0.840 46.080 252.560 ;
      RECT 48.040 0.840 48.320 252.560 ;
      RECT 50.280 0.840 50.560 252.560 ;
      RECT 52.520 0.840 52.800 252.560 ;
      RECT 54.760 0.840 55.040 252.560 ;
      RECT 57.000 0.840 57.280 252.560 ;
      RECT 59.240 0.840 59.520 252.560 ;
      RECT 61.480 0.840 61.760 252.560 ;
      RECT 63.720 0.840 64.000 252.560 ;
      RECT 65.960 0.840 66.240 252.560 ;
      RECT 68.200 0.840 68.480 252.560 ;
      RECT 70.440 0.840 70.720 252.560 ;
      RECT 72.680 0.840 72.960 252.560 ;
      RECT 74.920 0.840 75.200 252.560 ;
      RECT 77.160 0.840 77.440 252.560 ;
      RECT 79.400 0.840 79.680 252.560 ;
      RECT 81.640 0.840 81.920 252.560 ;
      RECT 83.880 0.840 84.160 252.560 ;
      RECT 86.120 0.840 86.400 252.560 ;
      RECT 88.360 0.840 88.640 252.560 ;
      RECT 90.600 0.840 90.880 252.560 ;
      RECT 92.840 0.840 93.120 252.560 ;
      RECT 95.080 0.840 95.360 252.560 ;
      RECT 97.320 0.840 97.600 252.560 ;
      RECT 99.560 0.840 99.840 252.560 ;
      RECT 101.800 0.840 102.080 252.560 ;
      RECT 104.040 0.840 104.320 252.560 ;
      RECT 106.280 0.840 106.560 252.560 ;
      RECT 108.520 0.840 108.800 252.560 ;
      RECT 110.760 0.840 111.040 252.560 ;
      RECT 113.000 0.840 113.280 252.560 ;
      RECT 115.240 0.840 115.520 252.560 ;
      RECT 117.480 0.840 117.760 252.560 ;
      RECT 119.720 0.840 120.000 252.560 ;
      RECT 121.960 0.840 122.240 252.560 ;
      RECT 124.200 0.840 124.480 252.560 ;
      RECT 126.440 0.840 126.720 252.560 ;
      RECT 128.680 0.840 128.960 252.560 ;
      RECT 130.920 0.840 131.200 252.560 ;
      RECT 133.160 0.840 133.440 252.560 ;
      RECT 135.400 0.840 135.680 252.560 ;
      RECT 137.640 0.840 137.920 252.560 ;
      RECT 139.880 0.840 140.160 252.560 ;
      RECT 142.120 0.840 142.400 252.560 ;
      RECT 144.360 0.840 144.640 252.560 ;
      RECT 146.600 0.840 146.880 252.560 ;
      RECT 148.840 0.840 149.120 252.560 ;
      RECT 151.080 0.840 151.360 252.560 ;
    END
  END VSS
  PIN VDD
    DIRECTION INOUT ;
    USE POWER ;
    PORT
      LAYER metal4 ;
      RECT 2.120 0.840 2.400 252.560 ;
      RECT 4.360 0.840 4.640 252.560 ;
      RECT 6.600 0.840 6.880 252.560 ;
      RECT 8.840 0.840 9.120 252.560 ;
      RECT 11.080 0.840 11.360 252.560 ;
      RECT 13.320 0.840 13.600 252.560 ;
      RECT 15.560 0.840 15.840 252.560 ;
      RECT 17.800 0.840 18.080 252.560 ;
      RECT 20.040 0.840 20.320 252.560 ;
      RECT 22.280 0.840 22.560 252.560 ;
      RECT 24.520 0.840 24.800 252.560 ;
      RECT 26.760 0.840 27.040 252.560 ;
      RECT 29.000 0.840 29.280 252.560 ;
      RECT 31.240 0.840 31.520 252.560 ;
      RECT 33.480 0.840 33.760 252.560 ;
      RECT 35.720 0.840 36.000 252.560 ;
      RECT 37.960 0.840 38.240 252.560 ;
      RECT 40.200 0.840 40.480 252.560 ;
      RECT 42.440 0.840 42.720 252.560 ;
      RECT 44.680 0.840 44.960 252.560 ;
      RECT 46.920 0.840 47.200 252.560 ;
      RECT 49.160 0.840 49.440 252.560 ;
      RECT 51.400 0.840 51.680 252.560 ;
      RECT 53.640 0.840 53.920 252.560 ;
      RECT 55.880 0.840 56.160 252.560 ;
      RECT 58.120 0.840 58.400 252.560 ;
      RECT 60.360 0.840 60.640 252.560 ;
      RECT 62.600 0.840 62.880 252.560 ;
      RECT 64.840 0.840 65.120 252.560 ;
      RECT 67.080 0.840 67.360 252.560 ;
      RECT 69.320 0.840 69.600 252.560 ;
      RECT 71.560 0.840 71.840 252.560 ;
      RECT 73.800 0.840 74.080 252.560 ;
      RECT 76.040 0.840 76.320 252.560 ;
      RECT 78.280 0.840 78.560 252.560 ;
      RECT 80.520 0.840 80.800 252.560 ;
      RECT 82.760 0.840 83.040 252.560 ;
      RECT 85.000 0.840 85.280 252.560 ;
      RECT 87.240 0.840 87.520 252.560 ;
      RECT 89.480 0.840 89.760 252.560 ;
      RECT 91.720 0.840 92.000 252.560 ;
      RECT 93.960 0.840 94.240 252.560 ;
      RECT 96.200 0.840 96.480 252.560 ;
      RECT 98.440 0.840 98.720 252.560 ;
      RECT 100.680 0.840 100.960 252.560 ;
      RECT 102.920 0.840 103.200 252.560 ;
      RECT 105.160 0.840 105.440 252.560 ;
      RECT 107.400 0.840 107.680 252.560 ;
      RECT 109.640 0.840 109.920 252.560 ;
      RECT 111.880 0.840 112.160 252.560 ;
      RECT 114.120 0.840 114.400 252.560 ;
      RECT 116.360 0.840 116.640 252.560 ;
      RECT 118.600 0.840 118.880 252.560 ;
      RECT 120.840 0.840 121.120 252.560 ;
      RECT 123.080 0.840 123.360 252.560 ;
      RECT 125.320 0.840 125.600 252.560 ;
      RECT 127.560 0.840 127.840 252.560 ;
      RECT 129.800 0.840 130.080 252.560 ;
      RECT 132.040 0.840 132.320 252.560 ;
      RECT 134.280 0.840 134.560 252.560 ;
      RECT 136.520 0.840 136.800 252.560 ;
      RECT 138.760 0.840 139.040 252.560 ;
      RECT 141.000 0.840 141.280 252.560 ;
      RECT 143.240 0.840 143.520 252.560 ;
      RECT 145.480 0.840 145.760 252.560 ;
      RECT 147.720 0.840 148.000 252.560 ;
      RECT 149.960 0.840 150.240 252.560 ;
    END
  END VDD
  OBS
    LAYER metal1 ;
    RECT 0 0 151.430 253.400 ;
    LAYER metal2 ;
    RECT 0 0 151.430 253.400 ;
    LAYER metal3 ;
    RECT 0 0 151.430 253.400 ;
    LAYER metal4 ;
    RECT 0 0 151.430 253.400 ;
    LAYER OVERLAP ;
    RECT 0 0 151.430 253.400 ;
  END
END fakeram_64x256_1r1w

END LIBRARY
